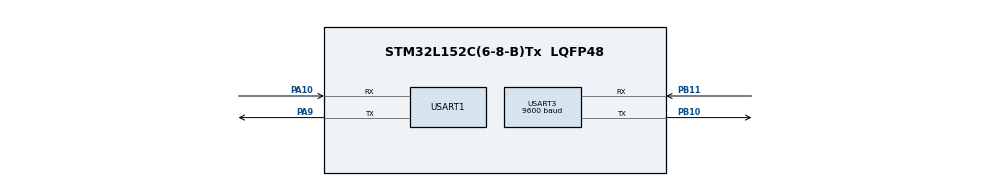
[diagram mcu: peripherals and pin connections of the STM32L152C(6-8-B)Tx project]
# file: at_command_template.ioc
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Dma.Request0=USART3_RX
Dma.Request1=USART3_TX
Dma.USART3_RX.0.Direction=DMA_PERIPH_TO_MEMORY
Dma.USART3_RX.0.Instance=DMA1_Channel3
Dma.USART3_RX.0.MemDataAlignment=DMA_MDATAALIGN_BYTE
Dma.USART3_RX.0.MemInc=DMA_MINC_ENABLE
Dma.USART3_RX.0.Mode=DMA_NORMAL
Dma.USART3_RX.0.PeriphDataAlignment=DMA_PDATAALIGN_BYTE
Dma.USART3_RX.0.PeriphInc=DMA_PINC_DISABLE
Dma.USART3_RX.0.Priority=DMA_PRIORITY_HIGH
Dma.USART3_TX.1.Direction=DMA_MEMORY_TO_PERIPH
Dma.USART3_TX.1.Instance=DMA1_Channel2
Dma.USART3_TX.1.MemDataAlignment=DMA_MDATAALIGN_BYTE
Dma.USART3_TX.1.MemInc=DMA_MINC_ENABLE
Dma.USART3_TX.1.Mode=DMA_NORMAL
Dma.USART3_TX.1.PeriphDataAlignment=DMA_PDATAALIGN_BYTE
Dma.USART3_TX.1.PeriphInc=DMA_PINC_DISABLE
Dma.USART3_TX.1.Priority=DMA_PRIORITY_VERY_HIGH
FREERTOS.Tasks01=defaultTask,0,128,StartDefaultTask,Default,NULL
FREERTOS.configTICK_RATE_HZ=100
FREERTOS.configTOTAL_HEAP_SIZE=4096
FREERTOS.configUSE_COUNTING_SEMAPHORES=1
Mcu.Family=STM32L1
Mcu.Name=STM32L152C(6-8-B)Tx
Mcu.Package=LQFP48
NVIC.DMA1_Channel2_IRQn=true\:5\:0\:false\:false\:true\:true\:false
NVIC.DMA1_Channel3_IRQn=true\:5\:0\:false\:false\:true\:true\:false
NVIC.PriorityGroup=NVIC_PRIORITYGROUP_4
NVIC.TIM6_IRQn=true\:0\:0\:false\:false\:true\:false\:false
NVIC.TimeBase=TIM6_IRQn
NVIC.TimeBaseIP=TIM6
NVIC.USART3_IRQn=true\:5\:0\:true\:false\:true\:true\:true
PA10.Mode=Asynchronous
PA10.Signal=USART1_RX
PA13.Mode=Serial_Wire
PA13.Signal=SYS_JTMS-SWDIO
PA14.Mode=Serial_Wire
PA14.Signal=SYS_JTCK-SWCLK
PA9.Mode=Asynchronous
PA9.Signal=USART1_TX
PB10.Mode=Asynchronous
PB10.Signal=USART3_TX
PB11.Mode=Asynchronous
PB11.Signal=USART3_RX
ProjectManager.HeapSize=0x200
ProjectManager.StackSize=0x400
ProjectManager.TargetToolchain=Makefile
RCC.AHBFreq_Value=2097000
RCC.APB1Freq_Value=2097000
RCC.APB2Freq_Value=2097000
RCC.HSE_VALUE=24000000
RCC.HSI_VALUE=16000000
RCC.LSE_VALUE=32768
RCC.MSI_VALUE=2097000
RCC.SYSCLKFreq_VALUE=2097000
RCC.VCOOutputFreq_Value=48000000
USART1.VirtualMode=VM_ASYNC
USART3.BaudRate=9600
USART3.VirtualMode=VM_ASYNC
VP_FREERTOS_VS_ENABLE.Mode=Enabled
VP_SYS_VS_tim6.Mode=TIM6
board=custom

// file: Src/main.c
/**
  ******************************************************************************
  * @file           : main.c
  * @brief          : Main program body
  ******************************************************************************
  * This notice applies to any and all portions of this file
  * that are not between comment pairs USER CODE BEGIN and
  * USER CODE END. Other portions of this file, whether
  * inserted by the user or by software development tools
  * are owned by their respective copyright owners.
  *
  * Copyright (c) 2018 STMicroelectronics International N.V.
  * All rights reserved.
  *
  * Redistribution and use in source and binary forms, with or without
  * modification, are permitted, provided that the following conditions are met:
  *
  * 1. Redistribution of source code must retain the above copyright notice,
  *    this list of conditions and the following disclaimer.
  * 2. Redistributions in binary form must reproduce the above copyright notice,
  *    this list of conditions and the following disclaimer in the documentation
  *    and/or other materials provided with the distribution.
  * 3. Neither the name of STMicroelectronics nor the names of other
  *    contributors to this software may be used to endorse or promote products
  *    derived from this software without specific written permission.
  * 4. This software, including modifications and/or derivative works of this
  *    software, must execute solely and exclusively on microcontroller or
  *    microprocessor devices manufactured by or for STMicroelectronics.
  * 5. Redistribution and use of this software other than as permitted under
  *    this license is void and will automatically terminate your rights under
  *    this license.
  *
  * THIS SOFTWARE IS PROVIDED BY STMICROELECTRONICS AND CONTRIBUTORS "AS IS"
  * AND ANY EXPRESS, IMPLIED OR STATUTORY WARRANTIES, INCLUDING, BUT NOT
  * LIMITED TO, THE IMPLIED WARRANTIES OF MERCHANTABILITY, FITNESS FOR A
  * PARTICULAR PURPOSE AND NON-INFRINGEMENT OF THIRD PARTY INTELLECTUAL PROPERTY
  * RIGHTS ARE DISCLAIMED TO THE FULLEST EXTENT PERMITTED BY LAW. IN NO EVENT
  * SHALL STMICROELECTRONICS OR CONTRIBUTORS BE LIABLE FOR ANY DIRECT, INDIRECT,
  * INCIDENTAL, SPECIAL, EXEMPLARY, OR CONSEQUENTIAL DAMAGES (INCLUDING, BUT NOT
  * LIMITED TO, PROCUREMENT OF SUBSTITUTE GOODS OR SERVICES; LOSS OF USE, DATA,
  * OR PROFITS; OR BUSINESS INTERRUPTION) HOWEVER CAUSED AND ON ANY THEORY OF
  * LIABILITY, WHETHER IN CONTRACT, STRICT LIABILITY, OR TORT (INCLUDING
  * NEGLIGENCE OR OTHERWISE) ARISING IN ANY WAY OUT OF THE USE OF THIS SOFTWARE,
  * EVEN IF ADVISED OF THE POSSIBILITY OF SUCH DAMAGE.
  *
  ******************************************************************************
  */
#include "main.h"
#include "stm32l1xx_hal.h"
#include "at_command_set.h"
#include "logging.h"
#include "serial_bsp.h"
#include "cmsis_os.h"
#include <string.h>

/* USER CODE BEGIN Includes */
//#define SERIAL_TEST
/* USER CODE END Includes */

UART_HandleTypeDef huart1;
UART_HandleTypeDef huart3;
DMA_HandleTypeDef hdma_usart3_rx;
DMA_HandleTypeDef hdma_usart3_tx;

osThreadId defaultTaskHandle;

char buff[256];

/* USER CODE BEGIN PV */
/* Private variables ---------------------------------------------------------*/

/* USER CODE END PV */

void SystemClock_Config(void);
static void MX_GPIO_Init(void);
static void MX_DMA_Init(void);
static void MX_USART1_UART_Init(void);
static void MX_USART3_UART_Init(void);
void StartDefaultTask(void const * argument);

#ifdef SERIAL_TEST
void serial_test(void *arg);
#endif

/* USER CODE BEGIN PFP */
/* Private function prototypes -----------------------------------------------*/

/* USER CODE END PFP */

int main(void)
{

    /* MCU Configuration----------------------------------------------------------*/

    /* Reset of all peripherals, Initializes the Flash interface and the Systick. */
    HAL_Init();

    /* Configure the system clock */
    SystemClock_Config();

    /* Initialize all configured peripherals */
    MX_GPIO_Init();
    MX_DMA_Init();
    MX_USART1_UART_Init();
    MX_USART3_UART_Init();
    serial_init(&huart3);

    /* Create the thread(s) */
    /* definition and creation of defaultTask */
#ifdef SERIAL_TEST
    xTaskCreate(serial_test, "serial test", 128 * 3, NULL, 7, NULL);
#else
    osThreadDef(defaultTask, StartDefaultTask, osPriorityNormal, 0, 128 * 4);
    defaultTaskHandle = osThreadCreate(osThread(defaultTask), NULL);
#endif

    /* Start scheduler */
    osKernelStart();

    /* We should never get here as control is now taken by the scheduler */

    /* Infinite loop */
    while (1)
    {

    }

}

void SystemClock_Config(void)
{

    RCC_OscInitTypeDef RCC_OscInitStruct;
    RCC_ClkInitTypeDef RCC_ClkInitStruct;

    /**Configure the main internal regulator output voltage
    */
    __HAL_PWR_VOLTAGESCALING_CONFIG(PWR_REGULATOR_VOLTAGE_SCALE1);

    /**Initializes the CPU, AHB and APB busses clocks
      */
    RCC_OscInitStruct.OscillatorType = RCC_OSCILLATORTYPE_HSI;
    RCC_OscInitStruct.HSIState = RCC_HSI_ON;
    RCC_OscInitStruct.HSICalibrationValue = 16;
    RCC_OscInitStruct.PLL.PLLState = RCC_PLL_ON;
    RCC_OscInitStruct.PLL.PLLSource = RCC_PLLSOURCE_HSI;
    RCC_OscInitStruct.PLL.PLLMUL = RCC_PLL_MUL4;
    RCC_OscInitStruct.PLL.PLLDIV = RCC_PLL_DIV2;
    if (HAL_RCC_OscConfig(&RCC_OscInitStruct) != HAL_OK)
    {
        _Error_Handler(__FILE__, __LINE__);
    }

    /**Initializes the CPU, AHB and APB busses clocks
    */
    RCC_ClkInitStruct.ClockType = RCC_CLOCKTYPE_HCLK | RCC_CLOCKTYPE_SYSCLK
                                  | RCC_CLOCKTYPE_PCLK1 | RCC_CLOCKTYPE_PCLK2;
    RCC_ClkInitStruct.SYSCLKSource = RCC_SYSCLKSOURCE_PLLCLK;
    RCC_ClkInitStruct.AHBCLKDivider = RCC_SYSCLK_DIV1;
    RCC_ClkInitStruct.APB1CLKDivider = RCC_HCLK_DIV1;
    RCC_ClkInitStruct.APB2CLKDivider = RCC_HCLK_DIV1;

    if (HAL_RCC_ClockConfig(&RCC_ClkInitStruct, FLASH_LATENCY_1) != HAL_OK)
    {
        _Error_Handler(__FILE__, __LINE__);
    }

    /**Configure the Systick interrupt time
    */
    HAL_SYSTICK_Config(HAL_RCC_GetHCLKFreq() / 1000);

    /**Configure the Systick
    */
    HAL_SYSTICK_CLKSourceConfig(SYSTICK_CLKSOURCE_HCLK);

    /* SysTick_IRQn interrupt configuration */
    HAL_NVIC_SetPriority(SysTick_IRQn, 15, 0);
}

/* USART1 init function */
static void MX_USART1_UART_Init(void)
{

    huart1.Instance = USART1;
    huart1.Init.BaudRate = 115200 * 8;
    huart1.Init.WordLength = UART_WORDLENGTH_8B;
    huart1.Init.StopBits = UART_STOPBITS_1;
    huart1.Init.Parity = UART_PARITY_NONE;
    huart1.Init.Mode = UART_MODE_TX_RX;
    huart1.Init.HwFlowCtl = UART_HWCONTROL_NONE;
    huart1.Init.OverSampling = UART_OVERSAMPLING_16;
    if (HAL_UART_Init(&huart1) != HAL_OK)
    {
        _Error_Handler(__FILE__, __LINE__);
    }

}

/* USART3 init function */
static void MX_USART3_UART_Init(void)
{

    huart3.Instance = USART3;
    huart3.Init.BaudRate = 9600;
    huart3.Init.WordLength = UART_WORDLENGTH_8B;
    huart3.Init.StopBits = UART_STOPBITS_1;
    huart3.Init.Parity = UART_PARITY_NONE;
    huart3.Init.Mode = UART_MODE_TX_RX;
    huart3.Init.HwFlowCtl = UART_HWCONTROL_NONE;
    huart3.Init.OverSampling = UART_OVERSAMPLING_16;
    if (HAL_UART_Init(&huart3) != HAL_OK)
    {
        _Error_Handler(__FILE__, __LINE__);
    }

}

static void MX_DMA_Init(void)
{
    /* DMA controller clock enable */
    __HAL_RCC_DMA1_CLK_ENABLE();

    /* DMA interrupt init */
    /* DMA1_Channel2_IRQn interrupt configuration */
    HAL_NVIC_SetPriority(DMA1_Channel2_IRQn, 5, 0);
    HAL_NVIC_EnableIRQ(DMA1_Channel2_IRQn);
    /* DMA1_Channel3_IRQn interrupt configuration */
    HAL_NVIC_SetPriority(DMA1_Channel3_IRQn, 5, 0);
    HAL_NVIC_EnableIRQ(DMA1_Channel3_IRQn);

}

/** Configure pins as
        * Analog
        * Input
        * Output
        * EVENT_OUT
        * EXTI
*/
static void MX_GPIO_Init(void)
{

    /* GPIO Ports Clock Enable */
    __HAL_RCC_GPIOB_CLK_ENABLE();
    __HAL_RCC_GPIOA_CLK_ENABLE();

}

/* USER CODE BEGIN 4 */
void HAL_UART_RxCpltCallback(UART_HandleTypeDef *huart)
{
    if(huart->Instance == USART3)
    {
        serial_rxcplt_handler();
    }
}

/* USER CODE END 4 */

/* StartDefaultTask function */
void StartDefaultTask(void const * argument)
{
    int tmp[5];
    UNUSED(argument);
    /* USER CODE BEGIN 5 */
    /* Infinite loop */
    __Logging_I("at", "test start");
    for(;;)
    {
        at_read_command(AT_CGMI, buff);
        __Logging_I("at_read", "CGMI: %s", buff);
        osDelay(1000);
        at_read_command(AT_CSQ, tmp);
        __Logging_I("at_read", "CSQ: %d", tmp[0]);
        osDelay(1000);
    }
    /* USER CODE END 5 */
}

#ifdef SERIAL_TEST
const char TransmitData[][12] = {"at+csq", "at+cgmi"};
uint8_t TestBuff[512];
void serial_test(void *arg)
{
    UNUSED(arg);
    uint8_t i = 0;
    uint16_t len;

    while(1)
    {
        serial_write((uint8_t *)TransmitData[i % 2], strlen(TransmitData[i % 2]));
        len = serial_read(TestBuff, 256, 5000);
        TestBuff[len] = '\0';
        printf("%s\n", TestBuff);
        vTaskDelay(MS2TICK(1000));
        i++;
    }
}
#endif

void HAL_TIM_PeriodElapsedCallback(TIM_HandleTypeDef *htim)
{
    if (htim->Instance == TIM6)
    {
        HAL_IncTick();
    }
}

void _Error_Handler(char *file, int line)
{
    while(1)
    {
    }
}

/************************ (C) COPYRIGHT STMicroelectronics *****END OF FILE****/
